VERSION 5.7 ;
  NOWIREEXTENSIONATPIN ON ;
  DIVIDERCHAR "/" ;
  BUSBITCHARS "[]" ;
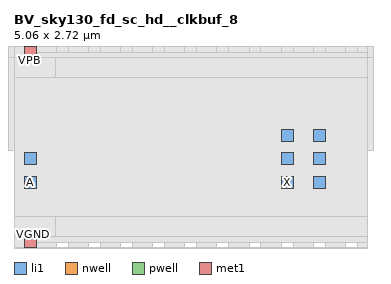
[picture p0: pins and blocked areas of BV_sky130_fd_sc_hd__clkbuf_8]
MACRO BV_sky130_fd_sc_hd__clkbuf_8
  CLASS BLOCK ;
  FOREIGN BV_sky130_fd_sc_hd__clkbuf_8 ;
  ORIGIN 0.000 0.000 ;
  SIZE 5.060 BY 2.720 ;
  PIN X
    PORT
      LAYER li1 ;
        RECT 3.825 1.445 3.995 1.615 ;
    END
    PORT
      LAYER li1 ;
        RECT 3.825 0.765 3.995 0.935 ;
    END
    PORT
      LAYER li1 ;
        RECT 4.285 0.765 4.455 0.935 ;
    END
    PORT
      LAYER li1 ;
        RECT 4.285 1.445 4.455 1.615 ;
    END
    PORT
      LAYER li1 ;
        RECT 3.825 1.105 3.995 1.275 ;
    END
    PORT
      LAYER li1 ;
        RECT 4.285 1.105 4.455 1.275 ;
    END
  END X
  PIN A
    PORT
      LAYER li1 ;
        RECT 0.145 0.765 0.315 0.935 ;
    END
    PORT
      LAYER li1 ;
        RECT 0.145 1.105 0.315 1.275 ;
    END
  END A
  PIN VPB
    PORT
      LAYER nwell ;
        RECT 0.145 2.635 0.315 2.805 ;
    END
  END VPB
  PIN VNB
    PORT
      LAYER pwell ;
        RECT 0.145 -0.085 0.315 0.085 ;
    END
  END VNB
  PIN VGND
    USE GROUND ;
    PORT
      LAYER met1 ;
        RECT 0.145 -0.085 0.315 0.085 ;
    END
  END VGND
  PIN VPWR
    USE POWER ;
    PORT
      LAYER met1 ;
        RECT 0.145 2.635 0.315 2.805 ;
    END
  END VPWR
  OBS
      LAYER nwell ;
        RECT -0.190 2.805 5.250 2.910 ;
        RECT -0.190 2.635 0.145 2.805 ;
        RECT 0.315 2.635 5.250 2.805 ;
        RECT -0.190 1.305 5.250 2.635 ;
        RECT 0.000 0.085 5.060 1.305 ;
      LAYER li1 ;
        RECT 0.000 2.720 0.145 2.805 ;
        RECT 0.315 2.720 0.605 2.805 ;
        RECT 0.775 2.720 1.065 2.805 ;
        RECT 1.235 2.720 1.525 2.805 ;
        RECT 1.695 2.720 1.985 2.805 ;
        RECT 2.155 2.720 2.445 2.805 ;
        RECT 2.615 2.720 2.905 2.805 ;
        RECT 3.075 2.720 3.365 2.805 ;
        RECT 3.535 2.720 3.825 2.805 ;
        RECT 3.995 2.720 4.285 2.805 ;
        RECT 4.455 2.720 4.745 2.805 ;
        RECT 4.915 2.720 5.060 2.805 ;
        RECT 0.000 1.785 5.060 2.720 ;
        RECT 0.000 1.445 3.655 1.785 ;
        RECT 0.485 0.595 3.655 1.445 ;
        RECT 4.625 0.595 5.060 1.785 ;
        RECT 0.000 0.000 5.060 0.595 ;
        RECT 0.000 -0.085 0.145 0.000 ;
        RECT 0.315 -0.085 0.605 0.000 ;
        RECT 0.775 -0.085 1.065 0.000 ;
        RECT 1.235 -0.085 1.525 0.000 ;
        RECT 1.695 -0.085 1.985 0.000 ;
        RECT 2.155 -0.085 2.445 0.000 ;
        RECT 2.615 -0.085 2.905 0.000 ;
        RECT 3.075 -0.085 3.365 0.000 ;
        RECT 3.535 -0.085 3.825 0.000 ;
        RECT 3.995 -0.085 4.285 0.000 ;
        RECT 4.455 -0.085 4.745 0.000 ;
        RECT 4.915 -0.085 5.060 0.000 ;
      LAYER met1 ;
        RECT 0.000 2.805 5.060 2.960 ;
        RECT 0.000 2.635 0.145 2.805 ;
        RECT 0.315 2.720 0.605 2.805 ;
        RECT 0.775 2.720 1.065 2.805 ;
        RECT 1.235 2.720 1.525 2.805 ;
        RECT 1.695 2.720 1.985 2.805 ;
        RECT 2.155 2.720 2.445 2.805 ;
        RECT 2.615 2.720 2.905 2.805 ;
        RECT 3.075 2.720 3.365 2.805 ;
        RECT 3.535 2.720 3.825 2.805 ;
        RECT 3.995 2.720 4.285 2.805 ;
        RECT 4.455 2.720 4.745 2.805 ;
        RECT 4.915 2.720 5.060 2.805 ;
        RECT 0.315 2.635 5.060 2.720 ;
        RECT 0.595 2.355 5.060 2.635 ;
        RECT 0.000 0.365 5.060 2.355 ;
        RECT 0.595 0.085 5.060 0.365 ;
        RECT 0.000 -0.085 0.145 0.085 ;
        RECT 0.315 0.000 5.060 0.085 ;
        RECT 0.315 -0.085 0.605 0.000 ;
        RECT 0.775 -0.085 1.065 0.000 ;
        RECT 1.235 -0.085 1.525 0.000 ;
        RECT 1.695 -0.085 1.985 0.000 ;
        RECT 2.155 -0.085 2.445 0.000 ;
        RECT 2.615 -0.085 2.905 0.000 ;
        RECT 3.075 -0.085 3.365 0.000 ;
        RECT 3.535 -0.085 3.825 0.000 ;
        RECT 3.995 -0.085 4.285 0.000 ;
        RECT 4.455 -0.085 4.745 0.000 ;
        RECT 4.915 -0.085 5.060 0.000 ;
        RECT 0.000 -0.240 5.060 -0.085 ;
  END
END BV_sky130_fd_sc_hd__clkbuf_8
END LIBRARY

